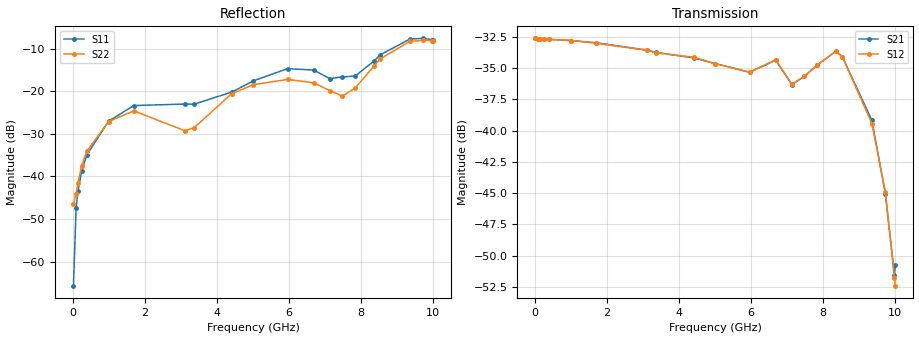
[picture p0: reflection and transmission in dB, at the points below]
! Device ID: PE43704
! Dir: z:\PE43704\PE43704_Char_1_20130516\PE43704\AMB\3p400V\31p75dB
! Serial: 14
! Insertion: A
! Impedance: 50 ohm
! Temp: Amb
! VDD: 3.400V
! Attenuation Step: 31.75dB
! IDD: 1.141024e-01mA
#  Hz  S  RI  R  50
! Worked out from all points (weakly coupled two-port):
!   401 points, 10 MHz to 10.01 GHz, reference 50 ohm
!   highest |S21| = -32.63 dB at 10 MHz (marker M1); lowest = -51.5 dB at 9.985 GHz (marker M2)
!   lowest |S11| = -65.7 dB at 10 MHz (marker M3), VSWR 1.00, Z = 50 + j0.0481 ohm
!   |S11| at or under -10 dB: start of sweep to 8.738 GHz
!   |S22| runs from -46.4 to -7.9 dB; largest |S21 - S12| = 0.00065
!   S11 on the Smith chart (normalised r, x): 10 MHz: 1.00, +0.00; 7.485 GHz: 0.78, +0.15; 8.535 GHz: 0.79, +0.45; 9.36 GHz: 0.54, +0.48; 10.01 GHz: 0.46, +0.27
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1e7  -0.000198 0.000481  0.0234 -8.37e-05  0.0234 -4.56e-05  -0.00479 0.000462
8.5e7  -0.000112 0.0043  0.0233 -0.000472  0.0233 -0.00048  -0.00442 0.0045
1.35e8  -0.000327 0.00666  0.0233 -0.00073  0.0233 -0.000721  -0.0046 0.00694
2.35e8  -0.00198 0.0113  0.0232 -0.00125  0.0232 -0.00126  -0.00591 0.0118
3.85e8  -0.00505 0.0173  0.0231 -0.00203  0.0231 -0.00201  -0.00878 0.0179
9.85e8  -0.0331 0.0299  0.0224 -0.00495  0.0224 -0.00496  -0.0329 0.0296
1.685e9  -0.0665 0.0151  0.021 -0.00802  0.0209 -0.00802  -0.0574 0.0139
3.11e9  -0.0708 -0.00663  0.0166 -0.0129  0.0165 -0.0129  -0.0333 0.00892
3.36e9  -0.0707 -0.000783  0.0155 -0.0135  0.0155 -0.0134  -0.0332 0.0171
4.41e9  -0.0882 0.0435  0.0124 -0.0151  0.0125 -0.0152  -0.0749 0.0572
5.01e9  -0.112 0.0721  0.0109 -0.015  0.011 -0.0149  -0.1056 0.0571
5.96e9  -0.1593 0.0949  0.00789 -0.0152  0.00794 -0.0152  -0.1312 0.0441
6.685e9  -0.1591 0.0804  0.00725 -0.0177  0.00723 -0.0178  -0.1215 0.0352
7.135e9  -0.1291 0.0575  0.00346 -0.0149  0.00366 -0.0149  -0.0916 0.0453
7.485e9  -0.1151 0.0934  0.00398 -0.016  0.00414 -0.016  -0.0653 0.0591
7.835e9  -0.0718 0.1334  0.00463 -0.0177  0.00458 -0.0177  -0.0523 0.096
8.36e9  -0.0406 0.2234  -0.00275 -0.0206  -0.00263 -0.0206  -0.072 0.1844
8.535e9  -0.049 0.2653  -0.0055 -0.019  -0.00517 -0.0191  -0.0928 0.2233
9.36e9  -0.1878 0.3676  -0.00848 -0.00698  -0.00845 -0.00649  -0.2507 0.2973
9.735e9  -0.2754 0.3179  -0.00459 -0.00313  -0.00453 -0.00343  -0.3298 0.2236
9.985e9  -0.3192 0.2496  -0.00081 -0.00252  -0.000748 -0.00246  -0.3689 0.144
1.001e10  -0.3249 0.2413  -0.000183 -0.00289  -0.000524 -0.00234  -0.3728 0.1353
